VERSION 5.7 ;
  NOWIREEXTENSIONATPIN ON ;
  DIVIDERCHAR "/" ;
  BUSBITCHARS "[]" ;
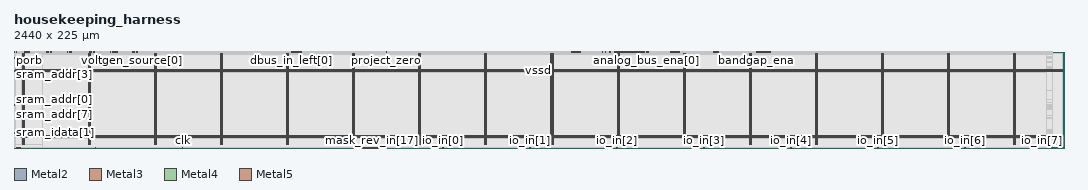
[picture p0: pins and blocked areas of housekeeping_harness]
MACRO housekeeping_harness
  CLASS BLOCK ;
  FOREIGN housekeeping_harness ;
  ORIGIN 0.000 0.000 ;
  SIZE 2440.000 BY 225.000 ;
  PIN CSB
    DIRECTION INPUT ;
    USE SIGNAL ;
    ANTENNAGATEAREA 0.666400 ;
    PORT
      LAYER Metal2 ;
        RECT 13.850 0.000 14.150 2.000 ;
    END
  END CSB
  PIN SCK
    DIRECTION INPUT ;
    USE SIGNAL ;
    ANTENNAGATEAREA 4.704000 ;
    PORT
      LAYER Metal2 ;
        RECT 188.850 0.000 189.150 2.000 ;
    END
  END SCK
  PIN SDI
    DIRECTION INPUT ;
    USE SIGNAL ;
    ANTENNAGATEAREA 0.666400 ;
    PORT
      LAYER Metal2 ;
        RECT 10.850 0.000 11.150 2.000 ;
    END
  END SDI
  PIN SDO
    DIRECTION OUTPUT ;
    USE SIGNAL ;
    ANTENNAGATEAREA 0.666400 ;
    ANTENNADIFFAREA 1.237600 ;
    PORT
      LAYER Metal2 ;
        RECT 4.850 0.000 5.150 2.000 ;
    END
  END SDO
  PIN analog_bus_ena[0]
    DIRECTION OUTPUT ;
    USE SIGNAL ;
    ANTENNADIFFAREA 4.368000 ;
    PORT
      LAYER Metal2 ;
        RECT 1468.850 223.000 1469.150 225.000 ;
    END
  END analog_bus_ena[0]
  PIN analog_bus_ena[1]
    DIRECTION OUTPUT ;
    USE SIGNAL ;
    ANTENNADIFFAREA 4.368000 ;
    PORT
      LAYER Metal2 ;
        RECT 1470.850 223.000 1471.150 225.000 ;
    END
  END analog_bus_ena[1]
  PIN analog_bus_ena[2]
    DIRECTION OUTPUT ;
    USE SIGNAL ;
    ANTENNADIFFAREA 4.368000 ;
    PORT
      LAYER Metal2 ;
        RECT 1472.850 223.000 1473.150 225.000 ;
    END
  END analog_bus_ena[2]
  PIN analog_bus_ena[3]
    DIRECTION OUTPUT ;
    USE SIGNAL ;
    ANTENNADIFFAREA 4.368000 ;
    PORT
      LAYER Metal2 ;
        RECT 1474.850 223.000 1475.150 225.000 ;
    END
  END analog_bus_ena[3]
  PIN bandgap_ena
    DIRECTION OUTPUT ;
    USE SIGNAL ;
    ANTENNADIFFAREA 1.237600 ;
    PORT
      LAYER Metal2 ;
        RECT 1724.850 223.000 1725.150 225.000 ;
    END
  END bandgap_ena
  PIN bandgap_sink1[0]
    DIRECTION OUTPUT ;
    USE SIGNAL ;
    ANTENNADIFFAREA 1.237600 ;
    PORT
      LAYER Metal2 ;
        RECT 174.850 223.000 175.150 225.000 ;
    END
  END bandgap_sink1[0]
  PIN bandgap_sink1[1]
    DIRECTION OUTPUT ;
    USE SIGNAL ;
    ANTENNADIFFAREA 1.237600 ;
    PORT
      LAYER Metal2 ;
        RECT 177.850 223.000 178.150 225.000 ;
    END
  END bandgap_sink1[1]
  PIN bandgap_sink1[2]
    DIRECTION OUTPUT ;
    USE SIGNAL ;
    ANTENNADIFFAREA 1.237600 ;
    PORT
      LAYER Metal2 ;
        RECT 180.850 223.000 181.150 225.000 ;
    END
  END bandgap_sink1[2]
  PIN bandgap_sink2[0]
    DIRECTION OUTPUT ;
    USE SIGNAL ;
    ANTENNADIFFAREA 1.237600 ;
    PORT
      LAYER Metal2 ;
        RECT 183.850 223.000 184.150 225.000 ;
    END
  END bandgap_sink2[0]
  PIN bandgap_sink2[1]
    DIRECTION OUTPUT ;
    USE SIGNAL ;
    ANTENNADIFFAREA 1.237600 ;
    PORT
      LAYER Metal2 ;
        RECT 186.850 223.000 187.150 225.000 ;
    END
  END bandgap_sink2[1]
  PIN bandgap_trim[0]
    DIRECTION OUTPUT ;
    USE SIGNAL ;
    ANTENNADIFFAREA 1.237600 ;
    PORT
      LAYER Metal2 ;
        RECT 1726.850 223.000 1727.150 225.000 ;
    END
  END bandgap_trim[0]
  PIN bandgap_trim[10]
    DIRECTION OUTPUT ;
    USE SIGNAL ;
    ANTENNADIFFAREA 1.237600 ;
    PORT
      LAYER Metal2 ;
        RECT 1746.850 223.000 1747.150 225.000 ;
    END
  END bandgap_trim[10]
  PIN bandgap_trim[11]
    DIRECTION OUTPUT ;
    USE SIGNAL ;
    ANTENNADIFFAREA 1.237600 ;
    PORT
      LAYER Metal2 ;
        RECT 1748.850 223.000 1749.150 225.000 ;
    END
  END bandgap_trim[11]
  PIN bandgap_trim[12]
    DIRECTION OUTPUT ;
    USE SIGNAL ;
    ANTENNADIFFAREA 1.237600 ;
    PORT
      LAYER Metal2 ;
        RECT 1750.850 223.000 1751.150 225.000 ;
    END
  END bandgap_trim[12]
  PIN bandgap_trim[13]
    DIRECTION OUTPUT ;
    USE SIGNAL ;
    ANTENNADIFFAREA 1.237600 ;
    PORT
      LAYER Metal2 ;
        RECT 1752.850 223.000 1753.150 225.000 ;
    END
  END bandgap_trim[13]
  PIN bandgap_trim[14]
    DIRECTION OUTPUT ;
    USE SIGNAL ;
    ANTENNADIFFAREA 1.237600 ;
    PORT
      LAYER Metal2 ;
        RECT 1754.850 223.000 1755.150 225.000 ;
    END
  END bandgap_trim[14]
  PIN bandgap_trim[15]
    DIRECTION OUTPUT ;
    USE SIGNAL ;
    ANTENNADIFFAREA 1.237600 ;
    PORT
      LAYER Metal2 ;
        RECT 1756.850 223.000 1757.150 225.000 ;
    END
  END bandgap_trim[15]
  PIN bandgap_trim[1]
    DIRECTION OUTPUT ;
    USE SIGNAL ;
    ANTENNADIFFAREA 1.237600 ;
    PORT
      LAYER Metal2 ;
        RECT 1728.850 223.000 1729.150 225.000 ;
    END
  END bandgap_trim[1]
  PIN bandgap_trim[2]
    DIRECTION OUTPUT ;
    USE SIGNAL ;
    ANTENNADIFFAREA 1.237600 ;
    PORT
      LAYER Metal2 ;
        RECT 1730.850 223.000 1731.150 225.000 ;
    END
  END bandgap_trim[2]
  PIN bandgap_trim[3]
    DIRECTION OUTPUT ;
    USE SIGNAL ;
    ANTENNADIFFAREA 1.237600 ;
    PORT
      LAYER Metal2 ;
        RECT 1732.850 223.000 1733.150 225.000 ;
    END
  END bandgap_trim[3]
  PIN bandgap_trim[4]
    DIRECTION OUTPUT ;
    USE SIGNAL ;
    ANTENNADIFFAREA 1.237600 ;
    PORT
      LAYER Metal2 ;
        RECT 1734.850 223.000 1735.150 225.000 ;
    END
  END bandgap_trim[4]
  PIN bandgap_trim[5]
    DIRECTION OUTPUT ;
    USE SIGNAL ;
    ANTENNADIFFAREA 1.237600 ;
    PORT
      LAYER Metal2 ;
        RECT 1736.850 223.000 1737.150 225.000 ;
    END
  END bandgap_trim[5]
  PIN bandgap_trim[6]
    DIRECTION OUTPUT ;
    USE SIGNAL ;
    ANTENNADIFFAREA 1.237600 ;
    PORT
      LAYER Metal2 ;
        RECT 1738.850 223.000 1739.150 225.000 ;
    END
  END bandgap_trim[6]
  PIN bandgap_trim[7]
    DIRECTION OUTPUT ;
    USE SIGNAL ;
    ANTENNADIFFAREA 1.237600 ;
    PORT
      LAYER Metal2 ;
        RECT 1740.850 223.000 1741.150 225.000 ;
    END
  END bandgap_trim[7]
  PIN bandgap_trim[8]
    DIRECTION OUTPUT ;
    USE SIGNAL ;
    ANTENNADIFFAREA 1.237600 ;
    PORT
      LAYER Metal2 ;
        RECT 1742.850 223.000 1743.150 225.000 ;
    END
  END bandgap_trim[8]
  PIN bandgap_trim[9]
    DIRECTION OUTPUT ;
    USE SIGNAL ;
    ANTENNADIFFAREA 1.237600 ;
    PORT
      LAYER Metal2 ;
        RECT 1744.850 223.000 1745.150 225.000 ;
    END
  END bandgap_trim[9]
  PIN biasgen_coarse
    DIRECTION OUTPUT ;
    USE SIGNAL ;
    ANTENNADIFFAREA 1.237600 ;
    PORT
      LAYER Metal2 ;
        RECT 127.850 223.000 128.150 225.000 ;
    END
  END biasgen_coarse
  PIN biasgen_ena
    DIRECTION OUTPUT ;
    USE SIGNAL ;
    ANTENNADIFFAREA 1.237600 ;
    PORT
      LAYER Metal2 ;
        RECT 124.850 223.000 125.150 225.000 ;
    END
  END biasgen_ena
  PIN biasgen_fine
    DIRECTION OUTPUT ;
    USE SIGNAL ;
    ANTENNADIFFAREA 1.237600 ;
    PORT
      LAYER Metal2 ;
        RECT 130.850 223.000 131.150 225.000 ;
    END
  END biasgen_fine
  PIN biasgen_ref_vbg
    DIRECTION OUTPUT ;
    USE SIGNAL ;
    ANTENNADIFFAREA 1.237600 ;
    PORT
      LAYER Metal2 ;
        RECT 133.850 223.000 134.150 225.000 ;
    END
  END biasgen_ref_vbg
  PIN clk
    DIRECTION INPUT ;
    USE SIGNAL ;
    ANTENNAGATEAREA 4.704000 ;
    PORT
      LAYER Metal2 ;
        RECT 391.850 0.000 392.150 2.000 ;
    END
  END clk
  PIN clk_out
    DIRECTION OUTPUT ;
    USE SIGNAL ;
    ANTENNADIFFAREA 6.583500 ;
    PORT
      LAYER Metal2 ;
        RECT 1374.850 223.000 1375.150 225.000 ;
    END
  END clk_out
  PIN dbus_in_left[0]
    DIRECTION INPUT ;
    USE SIGNAL ;
    ANTENNAGATEAREA 1.999200 ;
    ANTENNADIFFAREA 1.754000 ;
    PORT
      LAYER Metal2 ;
        RECT 644.850 223.000 645.150 225.000 ;
    END
  END dbus_in_left[0]
  PIN dbus_in_left[10]
    DIRECTION INPUT ;
    USE SIGNAL ;
    ANTENNAGATEAREA 1.999200 ;
    PORT
      LAYER Metal2 ;
        RECT 664.850 223.000 665.150 225.000 ;
    END
  END dbus_in_left[10]
  PIN dbus_in_left[11]
    DIRECTION INPUT ;
    USE SIGNAL ;
    ANTENNAGATEAREA 1.999200 ;
    PORT
      LAYER Metal2 ;
        RECT 666.850 223.000 667.150 225.000 ;
    END
  END dbus_in_left[11]
  PIN dbus_in_left[1]
    DIRECTION INPUT ;
    USE SIGNAL ;
    ANTENNAGATEAREA 1.999200 ;
    ANTENNADIFFAREA 1.754000 ;
    PORT
      LAYER Metal2 ;
        RECT 646.850 223.000 647.150 225.000 ;
    END
  END dbus_in_left[1]
  PIN dbus_in_left[2]
    DIRECTION INPUT ;
    USE SIGNAL ;
    ANTENNAGATEAREA 3.332000 ;
    PORT
      LAYER Metal2 ;
        RECT 648.850 223.000 649.150 225.000 ;
    END
  END dbus_in_left[2]
  PIN dbus_in_left[3]
    DIRECTION INPUT ;
    USE SIGNAL ;
    ANTENNAGATEAREA 1.999200 ;
    PORT
      LAYER Metal2 ;
        RECT 650.850 223.000 651.150 225.000 ;
    END
  END dbus_in_left[3]
  PIN dbus_in_left[4]
    DIRECTION INPUT ;
    USE SIGNAL ;
    ANTENNAGATEAREA 1.999200 ;
    ANTENNADIFFAREA 1.754000 ;
    PORT
      LAYER Metal2 ;
        RECT 652.850 223.000 653.150 225.000 ;
    END
  END dbus_in_left[4]
  PIN dbus_in_left[5]
    DIRECTION INPUT ;
    USE SIGNAL ;
    ANTENNAGATEAREA 1.999200 ;
    PORT
      LAYER Metal2 ;
        RECT 654.850 223.000 655.150 225.000 ;
    END
  END dbus_in_left[5]
  PIN dbus_in_left[6]
    DIRECTION INPUT ;
    USE SIGNAL ;
    ANTENNAGATEAREA 1.999200 ;
    ANTENNADIFFAREA 0.438500 ;
    PORT
      LAYER Metal2 ;
        RECT 656.850 223.000 657.150 225.000 ;
    END
  END dbus_in_left[6]
  PIN dbus_in_left[7]
    DIRECTION INPUT ;
    USE SIGNAL ;
    ANTENNAGATEAREA 1.999200 ;
    ANTENNADIFFAREA 1.754000 ;
    PORT
      LAYER Metal2 ;
        RECT 658.850 223.000 659.150 225.000 ;
    END
  END dbus_in_left[7]
  PIN dbus_in_left[8]
    DIRECTION INPUT ;
    USE SIGNAL ;
    ANTENNAGATEAREA 1.999200 ;
    PORT
      LAYER Metal2 ;
        RECT 660.850 223.000 661.150 225.000 ;
    END
  END dbus_in_left[8]
  PIN dbus_in_left[9]
    DIRECTION INPUT ;
    USE SIGNAL ;
    ANTENNAGATEAREA 1.999200 ;
    ANTENNADIFFAREA 1.754000 ;
    PORT
      LAYER Metal2 ;
        RECT 662.850 223.000 663.150 225.000 ;
    END
  END dbus_in_left[9]
  PIN dbus_in_right[0]
    DIRECTION INPUT ;
    USE SIGNAL ;
    ANTENNAGATEAREA 1.999200 ;
    PORT
      LAYER Metal2 ;
        RECT 1294.850 223.000 1295.150 225.000 ;
    END
  END dbus_in_right[0]
  PIN dbus_in_right[10]
    DIRECTION INPUT ;
    USE SIGNAL ;
    ANTENNAGATEAREA 1.999200 ;
    PORT
      LAYER Metal2 ;
        RECT 1314.850 223.000 1315.150 225.000 ;
    END
  END dbus_in_right[10]
  PIN dbus_in_right[11]
    DIRECTION INPUT ;
    USE SIGNAL ;
    ANTENNAGATEAREA 1.999200 ;
    PORT
      LAYER Metal2 ;
        RECT 1316.850 223.000 1317.150 225.000 ;
    END
  END dbus_in_right[11]
  PIN dbus_in_right[1]
    DIRECTION INPUT ;
    USE SIGNAL ;
    ANTENNAGATEAREA 1.999200 ;
    PORT
      LAYER Metal2 ;
        RECT 1296.850 223.000 1297.150 225.000 ;
    END
  END dbus_in_right[1]
  PIN dbus_in_right[2]
    DIRECTION INPUT ;
    USE SIGNAL ;
    ANTENNAGATEAREA 3.332000 ;
    PORT
      LAYER Metal2 ;
        RECT 1298.850 223.000 1299.150 225.000 ;
    END
  END dbus_in_right[2]
  PIN dbus_in_right[3]
    DIRECTION INPUT ;
    USE SIGNAL ;
    ANTENNAGATEAREA 1.999200 ;
    PORT
      LAYER Metal2 ;
        RECT 1300.850 223.000 1301.150 225.000 ;
    END
  END dbus_in_right[3]
  PIN dbus_in_right[4]
    DIRECTION INPUT ;
    USE SIGNAL ;
    ANTENNAGATEAREA 1.999200 ;
    PORT
      LAYER Metal2 ;
        RECT 1302.850 223.000 1303.150 225.000 ;
    END
  END dbus_in_right[4]
  PIN dbus_in_right[5]
    DIRECTION INPUT ;
    USE SIGNAL ;
    ANTENNAGATEAREA 1.999200 ;
    PORT
      LAYER Metal2 ;
        RECT 1304.850 223.000 1305.150 225.000 ;
    END
  END dbus_in_right[5]
  PIN dbus_in_right[6]
    DIRECTION INPUT ;
    USE SIGNAL ;
    ANTENNAGATEAREA 1.999200 ;
    PORT
      LAYER Metal2 ;
        RECT 1306.850 223.000 1307.150 225.000 ;
    END
  END dbus_in_right[6]
  PIN dbus_in_right[7]
    DIRECTION INPUT ;
    USE SIGNAL ;
    ANTENNAGATEAREA 1.999200 ;
    PORT
      LAYER Metal2 ;
        RECT 1308.850 223.000 1309.150 225.000 ;
    END
  END dbus_in_right[7]
  PIN dbus_in_right[8]
    DIRECTION INPUT ;
    USE SIGNAL ;
    ANTENNAGATEAREA 1.999200 ;
    PORT
      LAYER Metal2 ;
        RECT 1310.850 223.000 1311.150 225.000 ;
    END
  END dbus_in_right[8]
  PIN dbus_in_right[9]
    DIRECTION INPUT ;
    USE SIGNAL ;
    ANTENNAGATEAREA 1.999200 ;
    PORT
      LAYER Metal2 ;
        RECT 1312.850 223.000 1313.150 225.000 ;
    END
  END dbus_in_right[9]
  PIN dbus_out[0]
    DIRECTION OUTPUT ;
    USE SIGNAL ;
    ANTENNADIFFAREA 4.950400 ;
    PORT
      LAYER Metal2 ;
        RECT 1394.850 223.000 1395.150 225.000 ;
    END
  END dbus_out[0]
  PIN dbus_out[10]
    DIRECTION OUTPUT ;
    USE SIGNAL ;
    ANTENNADIFFAREA 4.950400 ;
    PORT
      LAYER Metal2 ;
        RECT 1414.850 223.000 1415.150 225.000 ;
    END
  END dbus_out[10]
  PIN dbus_out[11]
    DIRECTION OUTPUT ;
    USE SIGNAL ;
    ANTENNADIFFAREA 4.950400 ;
    PORT
      LAYER Metal2 ;
        RECT 1416.850 223.000 1417.150 225.000 ;
    END
  END dbus_out[11]
  PIN dbus_out[12]
    DIRECTION OUTPUT ;
    USE SIGNAL ;
    ANTENNADIFFAREA 4.950400 ;
    PORT
      LAYER Metal2 ;
        RECT 1418.850 223.000 1419.150 225.000 ;
    END
  END dbus_out[12]
  PIN dbus_out[13]
    DIRECTION OUTPUT ;
    USE SIGNAL ;
    ANTENNADIFFAREA 4.950400 ;
    PORT
      LAYER Metal2 ;
        RECT 1420.850 223.000 1421.150 225.000 ;
    END
  END dbus_out[13]
  PIN dbus_out[14]
    DIRECTION OUTPUT ;
    USE SIGNAL ;
    ANTENNADIFFAREA 4.950400 ;
    PORT
      LAYER Metal2 ;
        RECT 1422.850 223.000 1423.150 225.000 ;
    END
  END dbus_out[14]
  PIN dbus_out[15]
    DIRECTION OUTPUT ;
    USE SIGNAL ;
    ANTENNADIFFAREA 4.950400 ;
    PORT
      LAYER Metal2 ;
        RECT 1424.850 223.000 1425.150 225.000 ;
    END
  END dbus_out[15]
  PIN dbus_out[16]
    DIRECTION OUTPUT ;
    USE SIGNAL ;
    ANTENNADIFFAREA 4.950400 ;
    PORT
      LAYER Metal2 ;
        RECT 1426.850 223.000 1427.150 225.000 ;
    END
  END dbus_out[16]
  PIN dbus_out[17]
    DIRECTION OUTPUT ;
    USE SIGNAL ;
    ANTENNADIFFAREA 4.950400 ;
    PORT
      LAYER Metal2 ;
        RECT 1428.850 223.000 1429.150 225.000 ;
    END
  END dbus_out[17]
  PIN dbus_out[18]
    DIRECTION OUTPUT ;
    USE SIGNAL ;
    ANTENNADIFFAREA 4.950400 ;
    PORT
      LAYER Metal2 ;
        RECT 1430.850 223.000 1431.150 225.000 ;
    END
  END dbus_out[18]
  PIN dbus_out[19]
    DIRECTION OUTPUT ;
    USE SIGNAL ;
    ANTENNADIFFAREA 4.950400 ;
    PORT
      LAYER Metal2 ;
        RECT 1432.850 223.000 1433.150 225.000 ;
    END
  END dbus_out[19]
  PIN dbus_out[1]
    DIRECTION OUTPUT ;
    USE SIGNAL ;
    ANTENNADIFFAREA 4.950400 ;
    PORT
      LAYER Metal2 ;
        RECT 1396.850 223.000 1397.150 225.000 ;
    END
  END dbus_out[1]
  PIN dbus_out[20]
    DIRECTION OUTPUT ;
    USE SIGNAL ;
    ANTENNADIFFAREA 4.950400 ;
    PORT
      LAYER Metal2 ;
        RECT 1434.850 223.000 1435.150 225.000 ;
    END
  END dbus_out[20]
  PIN dbus_out[21]
    DIRECTION OUTPUT ;
    USE SIGNAL ;
    ANTENNADIFFAREA 4.950400 ;
    PORT
      LAYER Metal2 ;
        RECT 1436.850 223.000 1437.150 225.000 ;
    END
  END dbus_out[21]
  PIN dbus_out[22]
    DIRECTION OUTPUT ;
    USE SIGNAL ;
    ANTENNADIFFAREA 4.950400 ;
    PORT
      LAYER Metal2 ;
        RECT 1438.850 223.000 1439.150 225.000 ;
    END
  END dbus_out[22]
  PIN dbus_out[23]
    DIRECTION OUTPUT ;
    USE SIGNAL ;
    ANTENNADIFFAREA 4.950400 ;
    PORT
      LAYER Metal2 ;
        RECT 1440.850 223.000 1441.150 225.000 ;
    END
  END dbus_out[23]
  PIN dbus_out[2]
    DIRECTION OUTPUT ;
    USE SIGNAL ;
    ANTENNADIFFAREA 4.950400 ;
    PORT
      LAYER Metal2 ;
        RECT 1398.850 223.000 1399.150 225.000 ;
    END
  END dbus_out[2]
  PIN dbus_out[3]
    DIRECTION OUTPUT ;
    USE SIGNAL ;
    ANTENNADIFFAREA 4.950400 ;
    PORT
      LAYER Metal2 ;
        RECT 1400.850 223.000 1401.150 225.000 ;
    END
  END dbus_out[3]
  PIN dbus_out[4]
    DIRECTION OUTPUT ;
    USE SIGNAL ;
    ANTENNADIFFAREA 4.950400 ;
    PORT
      LAYER Metal2 ;
        RECT 1402.850 223.000 1403.150 225.000 ;
    END
  END dbus_out[4]
  PIN dbus_out[5]
    DIRECTION OUTPUT ;
    USE SIGNAL ;
    ANTENNADIFFAREA 4.950400 ;
    PORT
      LAYER Metal2 ;
        RECT 1404.850 223.000 1405.150 225.000 ;
    END
  END dbus_out[5]
  PIN dbus_out[6]
    DIRECTION OUTPUT ;
    USE SIGNAL ;
    ANTENNADIFFAREA 4.950400 ;
    PORT
      LAYER Metal2 ;
        RECT 1406.850 223.000 1407.150 225.000 ;
    END
  END dbus_out[6]
  PIN dbus_out[7]
    DIRECTION OUTPUT ;
    USE SIGNAL ;
    ANTENNADIFFAREA 4.950400 ;
    PORT
      LAYER Metal2 ;
        RECT 1408.850 223.000 1409.150 225.000 ;
    END
  END dbus_out[7]
  PIN dbus_out[8]
    DIRECTION OUTPUT ;
    USE SIGNAL ;
    ANTENNADIFFAREA 4.950400 ;
    PORT
      LAYER Metal2 ;
        RECT 1410.850 223.000 1411.150 225.000 ;
    END
  END dbus_out[8]
  PIN dbus_out[9]
    DIRECTION OUTPUT ;
    USE SIGNAL ;
    ANTENNADIFFAREA 4.950400 ;
    PORT
      LAYER Metal2 ;
        RECT 1412.850 223.000 1413.150 225.000 ;
    END
  END dbus_out[9]
  PIN idac1_value[0]
    DIRECTION OUTPUT ;
    USE SIGNAL ;
    ANTENNADIFFAREA 1.237600 ;
    PORT
      LAYER Metal2 ;
        RECT 24.850 223.000 25.150 225.000 ;
    END
  END idac1_value[0]
  PIN idac1_value[1]
    DIRECTION OUTPUT ;
    USE SIGNAL ;
    ANTENNADIFFAREA 1.237600 ;
    PORT
      LAYER Metal2 ;
        RECT 27.850 223.000 28.150 225.000 ;
    END
  END idac1_value[1]
  PIN idac1_value[2]
    DIRECTION OUTPUT ;
    USE SIGNAL ;
    ANTENNADIFFAREA 1.237600 ;
    PORT
      LAYER Metal2 ;
        RECT 30.850 223.000 31.150 225.000 ;
    END
  END idac1_value[2]
  PIN idac1_value[3]
    DIRECTION OUTPUT ;
    USE SIGNAL ;
    ANTENNADIFFAREA 1.237600 ;
    PORT
      LAYER Metal2 ;
        RECT 33.850 223.000 34.150 225.000 ;
    END
  END idac1_value[3]
  PIN idac1_value[4]
    DIRECTION OUTPUT ;
    USE SIGNAL ;
    ANTENNADIFFAREA 1.237600 ;
    PORT
      LAYER Metal2 ;
        RECT 36.850 223.000 37.150 225.000 ;
    END
  END idac1_value[4]
  PIN idac2_value[0]
    DIRECTION OUTPUT ;
    USE SIGNAL ;
    ANTENNADIFFAREA 1.237600 ;
    PORT
      LAYER Metal2 ;
        RECT 74.850 223.000 75.150 225.000 ;
    END
  END idac2_value[0]
  PIN idac2_value[1]
    DIRECTION OUTPUT ;
    USE SIGNAL ;
    ANTENNADIFFAREA 1.237600 ;
    PORT
      LAYER Metal2 ;
        RECT 77.850 223.000 78.150 225.000 ;
    END
  END idac2_value[1]
  PIN idac2_value[2]
    DIRECTION OUTPUT ;
    USE SIGNAL ;
    ANTENNADIFFAREA 1.237600 ;
    PORT
      LAYER Metal2 ;
        RECT 80.850 223.000 81.150 225.000 ;
    END
  END idac2_value[2]
  PIN idac2_value[3]
    DIRECTION OUTPUT ;
    USE SIGNAL ;
    ANTENNADIFFAREA 1.237600 ;
    PORT
      LAYER Metal2 ;
        RECT 83.850 223.000 84.150 225.000 ;
    END
  END idac2_value[3]
  PIN idac2_value[4]
    DIRECTION OUTPUT ;
    USE SIGNAL ;
    ANTENNADIFFAREA 1.237600 ;
    PORT
      LAYER Metal2 ;
        RECT 86.850 223.000 87.150 225.000 ;
    END
  END idac2_value[4]
  PIN io_in[0]
    DIRECTION INPUT ;
    USE SIGNAL ;
    ANTENNAGATEAREA 0.666400 ;
    PORT
      LAYER Metal2 ;
        RECT 997.850 0.000 998.150 2.000 ;
    END
  END io_in[0]
  PIN io_in[10]
    DIRECTION INPUT ;
    USE SIGNAL ;
    ANTENNAGATEAREA 1.332800 ;
    PORT
      LAYER Metal2 ;
        RECT 1540.850 223.000 1541.150 225.000 ;
    END
  END io_in[10]
  PIN io_in[11]
    DIRECTION INPUT ;
    USE SIGNAL ;
    ANTENNAGATEAREA 0.666400 ;
    PORT
      LAYER Metal2 ;
        RECT 1546.850 223.000 1547.150 225.000 ;
    END
  END io_in[11]
  PIN io_in[1]
    DIRECTION INPUT ;
    USE SIGNAL ;
    ANTENNAGATEAREA 0.666400 ;
    PORT
      LAYER Metal2 ;
        RECT 1199.850 0.000 1200.150 2.000 ;
    END
  END io_in[1]
  PIN io_in[2]
    DIRECTION INPUT ;
    USE SIGNAL ;
    ANTENNAGATEAREA 1.332800 ;
    PORT
      LAYER Metal2 ;
        RECT 1401.850 0.000 1402.150 2.000 ;
    END
  END io_in[2]
  PIN io_in[3]
    DIRECTION INPUT ;
    USE SIGNAL ;
    ANTENNAGATEAREA 0.666400 ;
    PORT
      LAYER Metal2 ;
        RECT 1603.850 0.000 1604.150 2.000 ;
    END
  END io_in[3]
  PIN io_in[4]
    DIRECTION INPUT ;
    USE SIGNAL ;
    ANTENNAGATEAREA 1.332800 ;
    PORT
      LAYER Metal2 ;
        RECT 1805.850 0.000 1806.150 2.000 ;
    END
  END io_in[4]
  PIN io_in[5]
    DIRECTION INPUT ;
    USE SIGNAL ;
    ANTENNAGATEAREA 1.332800 ;
    PORT
      LAYER Metal2 ;
        RECT 2007.850 0.000 2008.150 2.000 ;
    END
  END io_in[5]
  PIN io_in[6]
    DIRECTION INPUT ;
    USE SIGNAL ;
    ANTENNAGATEAREA 0.666400 ;
    PORT
      LAYER Metal2 ;
        RECT 2209.850 0.000 2210.150 2.000 ;
    END
  END io_in[6]
  PIN io_in[7]
    DIRECTION INPUT ;
    USE SIGNAL ;
    ANTENNAGATEAREA 0.666400 ;
    PORT
      LAYER Metal2 ;
        RECT 2411.850 0.000 2412.150 2.000 ;
    END
  END io_in[7]
  PIN io_in[8]
    DIRECTION INPUT ;
    USE SIGNAL ;
    ANTENNAGATEAREA 1.332800 ;
    ANTENNADIFFAREA 0.877000 ;
    PORT
      LAYER Metal2 ;
        RECT 1528.850 223.000 1529.150 225.000 ;
    END
  END io_in[8]
  PIN io_in[9]
    DIRECTION INPUT ;
    USE SIGNAL ;
    ANTENNAGATEAREA 1.332800 ;
    PORT
      LAYER Metal2 ;
        RECT 1534.850 223.000 1535.150 225.000 ;
    END
  END io_in[9]
  PIN io_oe[0]
    DIRECTION OUTPUT ;
    USE SIGNAL ;
    ANTENNADIFFAREA 1.237600 ;
    PORT
      LAYER Metal2 ;
        RECT 996.850 0.000 997.150 2.000 ;
    END
  END io_oe[0]
  PIN io_oe[10]
    DIRECTION OUTPUT ;
    USE SIGNAL ;
    ANTENNADIFFAREA 1.237600 ;
    PORT
      LAYER Metal2 ;
        RECT 1538.850 223.000 1539.150 225.000 ;
    END
  END io_oe[10]
  PIN io_oe[11]
    DIRECTION OUTPUT ;
    USE SIGNAL ;
    ANTENNADIFFAREA 1.237600 ;
    PORT
      LAYER Metal2 ;
        RECT 1544.850 223.000 1545.150 225.000 ;
    END
  END io_oe[11]
  PIN io_oe[1]
    DIRECTION OUTPUT ;
    USE SIGNAL ;
    ANTENNADIFFAREA 1.237600 ;
    PORT
      LAYER Metal2 ;
        RECT 1198.850 0.000 1199.150 2.000 ;
    END
  END io_oe[1]
  PIN io_oe[2]
    DIRECTION OUTPUT ;
    USE SIGNAL ;
    ANTENNADIFFAREA 1.237600 ;
    PORT
      LAYER Metal2 ;
        RECT 1400.850 0.000 1401.150 2.000 ;
    END
  END io_oe[2]
  PIN io_oe[3]
    DIRECTION OUTPUT ;
    USE SIGNAL ;
    ANTENNADIFFAREA 1.237600 ;
    PORT
      LAYER Metal2 ;
        RECT 1602.850 0.000 1603.150 2.000 ;
    END
  END io_oe[3]
  PIN io_oe[4]
    DIRECTION OUTPUT ;
    USE SIGNAL ;
    ANTENNADIFFAREA 1.237600 ;
    PORT
      LAYER Metal2 ;
        RECT 1804.850 0.000 1805.150 2.000 ;
    END
  END io_oe[4]
  PIN io_oe[5]
    DIRECTION OUTPUT ;
    USE SIGNAL ;
    ANTENNADIFFAREA 1.237600 ;
    PORT
      LAYER Metal2 ;
        RECT 2006.850 0.000 2007.150 2.000 ;
    END
  END io_oe[5]
  PIN io_oe[6]
    DIRECTION OUTPUT ;
    USE SIGNAL ;
    ANTENNADIFFAREA 1.237600 ;
    PORT
      LAYER Metal2 ;
        RECT 2208.850 0.000 2209.150 2.000 ;
    END
  END io_oe[6]
  PIN io_oe[7]
    DIRECTION OUTPUT ;
    USE SIGNAL ;
    ANTENNADIFFAREA 1.237600 ;
    PORT
      LAYER Metal2 ;
        RECT 2410.850 0.000 2411.150 2.000 ;
    END
  END io_oe[7]
  PIN io_oe[8]
    DIRECTION OUTPUT ;
    USE SIGNAL ;
    ANTENNADIFFAREA 1.237600 ;
    PORT
      LAYER Metal2 ;
        RECT 1526.850 223.000 1527.150 225.000 ;
    END
  END io_oe[8]
  PIN io_oe[9]
    DIRECTION OUTPUT ;
    USE SIGNAL ;
    ANTENNADIFFAREA 1.237600 ;
    PORT
      LAYER Metal2 ;
        RECT 1532.850 223.000 1533.150 225.000 ;
    END
  END io_oe[9]
  PIN io_out[0]
    DIRECTION OUTPUT ;
    USE SIGNAL ;
    ANTENNADIFFAREA 4.950400 ;
    PORT
      LAYER Metal2 ;
        RECT 995.850 0.000 996.150 2.000 ;
    END
  END io_out[0]
  PIN io_out[10]
    DIRECTION OUTPUT ;
    USE SIGNAL ;
    ANTENNADIFFAREA 1.237600 ;
    PORT
      LAYER Metal2 ;
        RECT 1536.850 223.000 1537.150 225.000 ;
    END
  END io_out[10]
  PIN io_out[11]
    DIRECTION OUTPUT ;
    USE SIGNAL ;
    ANTENNADIFFAREA 4.950400 ;
    PORT
      LAYER Metal2 ;
        RECT 1542.850 223.000 1543.150 225.000 ;
    END
  END io_out[11]
  PIN io_out[1]
    DIRECTION OUTPUT ;
    USE SIGNAL ;
    ANTENNADIFFAREA 4.950400 ;
    PORT
      LAYER Metal2 ;
        RECT 1197.850 0.000 1198.150 2.000 ;
    END
  END io_out[1]
  PIN io_out[2]
    DIRECTION OUTPUT ;
    USE SIGNAL ;
    ANTENNADIFFAREA 4.950400 ;
    PORT
      LAYER Metal2 ;
        RECT 1399.850 0.000 1400.150 2.000 ;
    END
  END io_out[2]
  PIN io_out[3]
    DIRECTION OUTPUT ;
    USE SIGNAL ;
    ANTENNADIFFAREA 4.950400 ;
    PORT
      LAYER Metal2 ;
        RECT 1601.850 0.000 1602.150 2.000 ;
    END
  END io_out[3]
  PIN io_out[4]
    DIRECTION OUTPUT ;
    USE SIGNAL ;
    ANTENNADIFFAREA 4.950400 ;
    PORT
      LAYER Metal2 ;
        RECT 1803.850 0.000 1804.150 2.000 ;
    END
  END io_out[4]
  PIN io_out[5]
    DIRECTION OUTPUT ;
    USE SIGNAL ;
    ANTENNADIFFAREA 4.950400 ;
    PORT
      LAYER Metal2 ;
        RECT 2005.850 0.000 2006.150 2.000 ;
    END
  END io_out[5]
  PIN io_out[6]
    DIRECTION OUTPUT ;
    USE SIGNAL ;
    ANTENNADIFFAREA 1.237600 ;
    PORT
      LAYER Metal2 ;
        RECT 2207.850 0.000 2208.150 2.000 ;
    END
  END io_out[6]
  PIN io_out[7]
    DIRECTION OUTPUT ;
    USE SIGNAL ;
    ANTENNADIFFAREA 4.950400 ;
    PORT
      LAYER Metal2 ;
        RECT 2409.850 0.000 2410.150 2.000 ;
    END
  END io_out[7]
  PIN io_out[8]
    DIRECTION OUTPUT ;
    USE SIGNAL ;
    ANTENNADIFFAREA 4.950400 ;
    PORT
      LAYER Metal2 ;
        RECT 1524.850 223.000 1525.150 225.000 ;
    END
  END io_out[8]
  PIN io_out[9]
    DIRECTION OUTPUT ;
    USE SIGNAL ;
    ANTENNADIFFAREA 4.950400 ;
    PORT
      LAYER Metal2 ;
        RECT 1530.850 223.000 1531.150 225.000 ;
    END
  END io_out[9]
  PIN mask_rev_in[0]
    DIRECTION INPUT ;
    USE SIGNAL ;
    ANTENNAGATEAREA 0.666400 ;
    PORT
      LAYER Metal2 ;
        RECT 866.850 0.000 867.150 2.000 ;
    END
  END mask_rev_in[0]
  PIN mask_rev_in[10]
    DIRECTION INPUT ;
    USE SIGNAL ;
    ANTENNAGATEAREA 0.666400 ;
    PORT
      LAYER Metal2 ;
        RECT 846.850 0.000 847.150 2.000 ;
    END
  END mask_rev_in[10]
  PIN mask_rev_in[11]
    DIRECTION INPUT ;
    USE SIGNAL ;
    ANTENNAGATEAREA 0.666400 ;
    PORT
      LAYER Metal2 ;
        RECT 844.850 0.000 845.150 2.000 ;
    END
  END mask_rev_in[11]
  PIN mask_rev_in[12]
    DIRECTION INPUT ;
    USE SIGNAL ;
    ANTENNAGATEAREA 0.666400 ;
    PORT
      LAYER Metal2 ;
        RECT 842.850 0.000 843.150 2.000 ;
    END
  END mask_rev_in[12]
  PIN mask_rev_in[13]
    DIRECTION INPUT ;
    USE SIGNAL ;
    ANTENNAGATEAREA 0.666400 ;
    PORT
      LAYER Metal2 ;
        RECT 840.850 0.000 841.150 2.000 ;
    END
  END mask_rev_in[13]
  PIN mask_rev_in[14]
    DIRECTION INPUT ;
    USE SIGNAL ;
    ANTENNAGATEAREA 0.666400 ;
    PORT
      LAYER Metal2 ;
        RECT 838.850 0.000 839.150 2.000 ;
    END
  END mask_rev_in[14]
  PIN mask_rev_in[15]
    DIRECTION INPUT ;
    USE SIGNAL ;
    ANTENNAGATEAREA 0.666400 ;
    PORT
      LAYER Metal2 ;
        RECT 836.850 0.000 837.150 2.000 ;
    END
  END mask_rev_in[15]
  PIN mask_rev_in[16]
    DIRECTION INPUT ;
    USE SIGNAL ;
    ANTENNAGATEAREA 0.666400 ;
    PORT
      LAYER Metal2 ;
        RECT 834.850 0.000 835.150 2.000 ;
    END
  END mask_rev_in[16]
  PIN mask_rev_in[17]
    DIRECTION INPUT ;
    USE SIGNAL ;
    ANTENNAGATEAREA 0.666400 ;
    PORT
      LAYER Metal2 ;
        RECT 832.850 0.000 833.150 2.000 ;
    END
  END mask_rev_in[17]
  PIN mask_rev_in[18]
    DIRECTION INPUT ;
    USE SIGNAL ;
    ANTENNAGATEAREA 0.666400 ;
    PORT
      LAYER Metal2 ;
        RECT 830.850 0.000 831.150 2.000 ;
    END
  END mask_rev_in[18]
  PIN mask_rev_in[19]
    DIRECTION INPUT ;
    USE SIGNAL ;
    ANTENNAGATEAREA 0.666400 ;
    PORT
      LAYER Metal2 ;
        RECT 828.850 0.000 829.150 2.000 ;
    END
  END mask_rev_in[19]
  PIN mask_rev_in[1]
    DIRECTION INPUT ;
    USE SIGNAL ;
    ANTENNAGATEAREA 0.666400 ;
    PORT
      LAYER Metal2 ;
        RECT 864.850 0.000 865.150 2.000 ;
    END
  END mask_rev_in[1]
  PIN mask_rev_in[20]
    DIRECTION INPUT ;
    USE SIGNAL ;
    ANTENNAGATEAREA 0.666400 ;
    PORT
      LAYER Metal2 ;
        RECT 826.850 0.000 827.150 2.000 ;
    END
  END mask_rev_in[20]
  PIN mask_rev_in[21]
    DIRECTION INPUT ;
    USE SIGNAL ;
    ANTENNAGATEAREA 0.666400 ;
    PORT
      LAYER Metal2 ;
        RECT 824.850 0.000 825.150 2.000 ;
    END
  END mask_rev_in[21]
  PIN mask_rev_in[22]
    DIRECTION INPUT ;
    USE SIGNAL ;
    ANTENNAGATEAREA 0.666400 ;
    PORT
      LAYER Metal2 ;
        RECT 822.850 0.000 823.150 2.000 ;
    END
  END mask_rev_in[22]
  PIN mask_rev_in[23]
    DIRECTION INPUT ;
    USE SIGNAL ;
    ANTENNAGATEAREA 0.666400 ;
    PORT
      LAYER Metal2 ;
        RECT 820.850 0.000 821.150 2.000 ;
    END
  END mask_rev_in[23]
  PIN mask_rev_in[24]
    DIRECTION INPUT ;
    USE SIGNAL ;
    ANTENNAGATEAREA 0.666400 ;
    ANTENNADIFFAREA 0.877000 ;
    PORT
      LAYER Metal2 ;
        RECT 818.850 0.000 819.150 2.000 ;
    END
  END mask_rev_in[24]
  PIN mask_rev_in[25]
    DIRECTION INPUT ;
    USE SIGNAL ;
    ANTENNAGATEAREA 0.666400 ;
    PORT
      LAYER Metal2 ;
        RECT 816.850 0.000 817.150 2.000 ;
    END
  END mask_rev_in[25]
  PIN mask_rev_in[26]
    DIRECTION INPUT ;
    USE SIGNAL ;
    ANTENNAGATEAREA 0.666400 ;
    PORT
      LAYER Metal2 ;
        RECT 814.850 0.000 815.150 2.000 ;
    END
  END mask_rev_in[26]
  PIN mask_rev_in[27]
    DIRECTION INPUT ;
    USE SIGNAL ;
    ANTENNAGATEAREA 0.666400 ;
    PORT
      LAYER Metal2 ;
        RECT 812.850 0.000 813.150 2.000 ;
    END
  END mask_rev_in[27]
  PIN mask_rev_in[28]
    DIRECTION INPUT ;
    USE SIGNAL ;
    ANTENNAGATEAREA 0.666400 ;
    PORT
      LAYER Metal2 ;
        RECT 810.850 0.000 811.150 2.000 ;
    END
  END mask_rev_in[28]
  PIN mask_rev_in[29]
    DIRECTION INPUT ;
    USE SIGNAL ;
    ANTENNAGATEAREA 0.666400 ;
    PORT
      LAYER Metal2 ;
        RECT 808.850 0.000 809.150 2.000 ;
    END
  END mask_rev_in[29]
  PIN mask_rev_in[2]
    DIRECTION INPUT ;
    USE SIGNAL ;
    ANTENNAGATEAREA 0.666400 ;
    PORT
      LAYER Metal2 ;
        RECT 862.850 0.000 863.150 2.000 ;
    END
  END mask_rev_in[2]
  PIN mask_rev_in[30]
    DIRECTION INPUT ;
    USE SIGNAL ;
    ANTENNAGATEAREA 0.666400 ;
    PORT
      LAYER Metal2 ;
        RECT 806.850 0.000 807.150 2.000 ;
    END
  END mask_rev_in[30]
  PIN mask_rev_in[31]
    DIRECTION INPUT ;
    USE SIGNAL ;
    ANTENNAGATEAREA 0.666400 ;
    PORT
      LAYER Metal2 ;
        RECT 804.850 0.000 805.150 2.000 ;
    END
  END mask_rev_in[31]
  PIN mask_rev_in[3]
    DIRECTION INPUT ;
    USE SIGNAL ;
    ANTENNAGATEAREA 0.666400 ;
    PORT
      LAYER Metal2 ;
        RECT 860.850 0.000 861.150 2.000 ;
    END
  END mask_rev_in[3]
  PIN mask_rev_in[4]
    DIRECTION INPUT ;
    USE SIGNAL ;
    ANTENNAGATEAREA 0.666400 ;
    PORT
      LAYER Metal2 ;
        RECT 858.850 0.000 859.150 2.000 ;
    END
  END mask_rev_in[4]
  PIN mask_rev_in[5]
    DIRECTION INPUT ;
    USE SIGNAL ;
    ANTENNAGATEAREA 0.666400 ;
    PORT
      LAYER Metal2 ;
        RECT 856.850 0.000 857.150 2.000 ;
    END
  END mask_rev_in[5]
  PIN mask_rev_in[6]
    DIRECTION INPUT ;
    USE SIGNAL ;
    ANTENNAGATEAREA 0.666400 ;
    PORT
      LAYER Metal2 ;
        RECT 854.850 0.000 855.150 2.000 ;
    END
  END mask_rev_in[6]
  PIN mask_rev_in[7]
    DIRECTION INPUT ;
    USE SIGNAL ;
    ANTENNAGATEAREA 0.666400 ;
    PORT
      LAYER Metal2 ;
        RECT 852.850 0.000 853.150 2.000 ;
    END
  END mask_rev_in[7]
  PIN mask_rev_in[8]
    DIRECTION INPUT ;
    USE SIGNAL ;
    ANTENNAGATEAREA 0.666400 ;
    ANTENNADIFFAREA 1.315500 ;
    PORT
      LAYER Metal2 ;
        RECT 850.850 0.000 851.150 2.000 ;
    END
  END mask_rev_in[8]
  PIN mask_rev_in[9]
    DIRECTION INPUT ;
    USE SIGNAL ;
    ANTENNAGATEAREA 0.666400 ;
    ANTENNADIFFAREA 1.315500 ;
    PORT
      LAYER Metal2 ;
        RECT 848.850 0.000 849.150 2.000 ;
    END
  END mask_rev_in[9]
  PIN porb
    DIRECTION INPUT ;
    USE SIGNAL ;
    ANTENNAGATEAREA 1.332800 ;
    ANTENNADIFFAREA 3.508000 ;
    PORT
      LAYER Metal2 ;
        RECT 4.850 223.000 5.150 225.000 ;
    END
  END porb
  PIN proj_3v3_ena
    DIRECTION OUTPUT ;
    USE SIGNAL ;
    ANTENNADIFFAREA 4.368000 ;
    PORT
      LAYER Metal2 ;
        RECT 1460.850 223.000 1461.150 225.000 ;
    END
  END proj_3v3_ena
  PIN proj_5v0_ena
    DIRECTION OUTPUT ;
    USE SIGNAL ;
    ANTENNADIFFAREA 4.368000 ;
    PORT
      LAYER Metal2 ;
        RECT 1458.850 223.000 1459.150 225.000 ;
    END
  END proj_5v0_ena
  PIN proj_dig_ena
    DIRECTION OUTPUT ;
    USE SIGNAL ;
    ANTENNADIFFAREA 4.368000 ;
    PORT
      LAYER Metal2 ;
        RECT 1456.850 223.000 1457.150 225.000 ;
    END
  END proj_dig_ena
  PIN proj_ena
    DIRECTION OUTPUT ;
    USE SIGNAL ;
    ANTENNADIFFAREA 4.368000 ;
    PORT
      LAYER Metal2 ;
        RECT 1454.850 223.000 1455.150 225.000 ;
    END
  END proj_ena
  PIN proj_ibias_ena[0]
    DIRECTION OUTPUT ;
    USE SIGNAL ;
    ANTENNADIFFAREA 4.368000 ;
    PORT
      LAYER Metal2 ;
        RECT 1462.850 223.000 1463.150 225.000 ;
    END
  END proj_ibias_ena[0]
  PIN proj_ibias_ena[1]
    DIRECTION OUTPUT ;
    USE SIGNAL ;
    ANTENNADIFFAREA 4.368000 ;
    PORT
      LAYER Metal2 ;
        RECT 1464.850 223.000 1465.150 225.000 ;
    END
  END proj_ibias_ena[1]
  PIN proj_sel[0]
    DIRECTION OUTPUT ;
    USE SIGNAL ;
    ANTENNADIFFAREA 4.368000 ;
    PORT
      LAYER Metal2 ;
        RECT 1444.850 223.000 1445.150 225.000 ;
    END
  END proj_sel[0]
  PIN proj_sel[1]
    DIRECTION OUTPUT ;
    USE SIGNAL ;
    ANTENNADIFFAREA 4.368000 ;
    PORT
      LAYER Metal2 ;
        RECT 1446.850 223.000 1447.150 225.000 ;
    END
  END proj_sel[1]
  PIN proj_sel[2]
    DIRECTION OUTPUT ;
    USE SIGNAL ;
    ANTENNADIFFAREA 4.368000 ;
    PORT
      LAYER Metal2 ;
        RECT 1448.850 223.000 1449.150 225.000 ;
    END
  END proj_sel[2]
  PIN proj_sel[3]
    DIRECTION OUTPUT ;
    USE SIGNAL ;
    ANTENNADIFFAREA 4.368000 ;
    PORT
      LAYER Metal2 ;
        RECT 1450.850 223.000 1451.150 225.000 ;
    END
  END proj_sel[3]
  PIN proj_sel[4]
    DIRECTION OUTPUT ;
    USE SIGNAL ;
    ANTENNADIFFAREA 4.368000 ;
    PORT
      LAYER Metal2 ;
        RECT 1452.850 223.000 1453.150 225.000 ;
    END
  END proj_sel[4]
  PIN proj_vbias_ena
    DIRECTION OUTPUT ;
    USE SIGNAL ;
    ANTENNADIFFAREA 4.368000 ;
    PORT
      LAYER Metal2 ;
        RECT 1366.850 223.000 1367.150 225.000 ;
    END
  END proj_vbias_ena
  PIN project_zero
    DIRECTION OUTPUT ;
    USE SIGNAL ;
    ANTENNADIFFAREA 1.237600 ;
    PORT
      LAYER Metal2 ;
        RECT 864.850 223.000 865.150 225.000 ;
    END
  END project_zero
  PIN reset
    DIRECTION OUTPUT ;
    USE SIGNAL ;
    ANTENNADIFFAREA 4.368000 ;
    PORT
      LAYER Metal2 ;
        RECT 1384.850 223.000 1385.150 225.000 ;
    END
  END reset
  PIN sdo_ena
    DIRECTION OUTPUT ;
    USE SIGNAL ;
    ANTENNADIFFAREA 1.237600 ;
    PORT
      LAYER Metal2 ;
        RECT 7.850 0.000 8.150 2.000 ;
    END
  END sdo_ena
  PIN sram_addr[0]
    DIRECTION OUTPUT ;
    USE SIGNAL ;
    ANTENNADIFFAREA 1.237600 ;
    PORT
      LAYER Metal3 ;
        RECT 0.000 111.850 2.000 112.150 ;
    END
  END sram_addr[0]
  PIN sram_addr[1]
    DIRECTION OUTPUT ;
    USE SIGNAL ;
    ANTENNADIFFAREA 1.237600 ;
    PORT
      LAYER Metal3 ;
        RECT 0.000 105.850 2.000 106.150 ;
    END
  END sram_addr[1]
  PIN sram_addr[2]
    DIRECTION OUTPUT ;
    USE SIGNAL ;
    ANTENNADIFFAREA 1.237600 ;
    PORT
      LAYER Metal3 ;
        RECT 0.000 99.850 2.000 100.150 ;
    END
  END sram_addr[2]
  PIN sram_addr[3]
    DIRECTION OUTPUT ;
    USE SIGNAL ;
    ANTENNADIFFAREA 1.237600 ;
    PORT
      LAYER Metal3 ;
        RECT 0.000 188.850 2.000 189.150 ;
    END
  END sram_addr[3]
  PIN sram_addr[4]
    DIRECTION OUTPUT ;
    USE SIGNAL ;
    ANTENNADIFFAREA 1.237600 ;
    PORT
      LAYER Metal3 ;
        RECT 0.000 184.850 2.000 185.150 ;
    END
  END sram_addr[4]
  PIN sram_addr[5]
    DIRECTION OUTPUT ;
    USE SIGNAL ;
    ANTENNADIFFAREA 1.237600 ;
    PORT
      LAYER Metal3 ;
        RECT 0.000 182.850 2.000 183.150 ;
    END
  END sram_addr[5]
  PIN sram_addr[6]
    DIRECTION OUTPUT ;
    USE SIGNAL ;
    ANTENNADIFFAREA 1.237600 ;
    PORT
      LAYER Metal3 ;
        RECT 0.000 180.850 2.000 181.150 ;
    END
  END sram_addr[6]
  PIN sram_addr[7]
    DIRECTION OUTPUT ;
    USE SIGNAL ;
    ANTENNADIFFAREA 1.237600 ;
    PORT
      LAYER Metal3 ;
        RECT 0.000 95.850 2.000 96.150 ;
    END
  END sram_addr[7]
  PIN sram_addr[8]
    DIRECTION OUTPUT ;
    USE SIGNAL ;
    ANTENNADIFFAREA 1.237600 ;
    PORT
      LAYER Metal3 ;
        RECT 0.000 93.850 2.000 94.150 ;
    END
  END sram_addr[8]
  PIN sram_addr[9]
    DIRECTION OUTPUT ;
    USE SIGNAL ;
    ANTENNADIFFAREA 1.237600 ;
    PORT
      LAYER Metal3 ;
        RECT 0.000 91.850 2.000 92.150 ;
    END
  END sram_addr[9]
  PIN sram_clk
    DIRECTION OUTPUT ;
    USE SIGNAL ;
    ANTENNADIFFAREA 1.285200 ;
    PORT
      LAYER Metal3 ;
        RECT 0.000 89.850 2.000 90.150 ;
    END
  END sram_clk
  PIN sram_idata[0]
    DIRECTION OUTPUT ;
    USE SIGNAL ;
    ANTENNADIFFAREA 1.237600 ;
    PORT
      LAYER Metal3 ;
        RECT 0.000 0.850 2.000 1.150 ;
    END
  END sram_idata[0]
  PIN sram_idata[1]
    DIRECTION OUTPUT ;
    USE SIGNAL ;
    ANTENNADIFFAREA 1.237600 ;
    PORT
      LAYER Metal3 ;
        RECT 0.000 34.850 2.000 35.150 ;
    END
  END sram_idata[1]
  PIN sram_idata[2]
    DIRECTION OUTPUT ;
    USE SIGNAL ;
    ANTENNADIFFAREA 1.237600 ;
    PORT
      LAYER Metal3 ;
        RECT 0.000 38.850 2.000 39.150 ;
    END
  END sram_idata[2]
  PIN sram_idata[3]
    DIRECTION OUTPUT ;
    USE SIGNAL ;
    ANTENNADIFFAREA 1.237600 ;
    PORT
      LAYER Metal3 ;
        RECT 0.000 74.850 2.000 75.150 ;
    END
  END sram_idata[3]
  PIN sram_idata[4]
    DIRECTION OUTPUT ;
    USE SIGNAL ;
    ANTENNADIFFAREA 1.237600 ;
    PORT
      LAYER Metal3 ;
        RECT 0.000 208.850 2.000 209.150 ;
    END
  END sram_idata[4]
  PIN sram_idata[5]
    DIRECTION OUTPUT ;
    USE SIGNAL ;
    ANTENNADIFFAREA 1.237600 ;
    PORT
      LAYER Metal3 ;
        RECT 0.000 181.850 2.000 182.150 ;
    END
  END sram_idata[5]
  PIN sram_idata[6]
    DIRECTION OUTPUT ;
    USE SIGNAL ;
    ANTENNADIFFAREA 1.237600 ;
    PORT
      LAYER Metal3 ;
        RECT 0.000 186.850 2.000 187.150 ;
    END
  END sram_idata[6]
  PIN sram_idata[7]
    DIRECTION OUTPUT ;
    USE SIGNAL ;
    ANTENNADIFFAREA 1.237600 ;
    PORT
      LAYER Metal3 ;
        RECT 0.000 222.850 2.000 223.150 ;
    END
  END sram_idata[7]
  PIN sram_odata[0]
    DIRECTION INPUT ;
    USE SIGNAL ;
    ANTENNAGATEAREA 1.999200 ;
    PORT
      LAYER Metal3 ;
        RECT 0.000 5.850 2.000 6.150 ;
    END
  END sram_odata[0]
  PIN sram_odata[1]
    DIRECTION INPUT ;
    USE SIGNAL ;
    ANTENNAGATEAREA 1.999200 ;
    PORT
      LAYER Metal3 ;
        RECT 0.000 32.850 2.000 33.150 ;
    END
  END sram_odata[1]
  PIN sram_odata[2]
    DIRECTION INPUT ;
    USE SIGNAL ;
    ANTENNAGATEAREA 1.999200 ;
    PORT
      LAYER Metal3 ;
        RECT 0.000 41.850 2.000 42.150 ;
    END
  END sram_odata[2]
  PIN sram_odata[3]
    DIRECTION INPUT ;
    USE SIGNAL ;
    ANTENNAGATEAREA 1.999200 ;
    ANTENNADIFFAREA 0.877000 ;
    PORT
      LAYER Metal3 ;
        RECT 0.000 69.850 2.000 70.150 ;
    END
  END sram_odata[3]
  PIN sram_odata[4]
    DIRECTION INPUT ;
    USE SIGNAL ;
    ANTENNAGATEAREA 1.999200 ;
    PORT
      LAYER Metal3 ;
        RECT 0.000 211.850 2.000 212.150 ;
    END
  END sram_odata[4]
  PIN sram_odata[5]
    DIRECTION INPUT ;
    USE SIGNAL ;
    ANTENNAGATEAREA 1.999200 ;
    PORT
      LAYER Metal3 ;
        RECT 0.000 178.850 2.000 179.150 ;
    END
  END sram_odata[5]
  PIN sram_odata[6]
    DIRECTION INPUT ;
    USE SIGNAL ;
    ANTENNAGATEAREA 1.999200 ;
    PORT
      LAYER Metal3 ;
        RECT 0.000 189.850 2.000 190.150 ;
    END
  END sram_odata[6]
  PIN sram_odata[7]
    DIRECTION INPUT ;
    USE SIGNAL ;
    ANTENNAGATEAREA 1.999200 ;
    PORT
      LAYER Metal3 ;
        RECT 0.000 217.850 2.000 218.150 ;
    END
  END sram_odata[7]
  PIN sram_read
    DIRECTION OUTPUT ;
    USE SIGNAL ;
    ANTENNADIFFAREA 1.439900 ;
    PORT
      LAYER Metal3 ;
        RECT 0.000 199.850 2.000 200.150 ;
    END
  END sram_read
  PIN sram_write
    DIRECTION OUTPUT ;
    USE SIGNAL ;
    ANTENNADIFFAREA 1.237600 ;
    PORT
      LAYER Metal3 ;
        RECT 0.000 133.850 2.000 134.150 ;
    END
  END sram_write
  PIN vddd
    DIRECTION INOUT ;
    USE POWER ;
    PORT
      LAYER Metal4 ;
        RECT 18.880 7.540 20.480 219.820 ;
    END
    PORT
      LAYER Metal4 ;
        RECT 172.480 7.540 174.080 219.820 ;
    END
    PORT
      LAYER Metal4 ;
        RECT 326.080 7.540 327.680 219.820 ;
    END
    PORT
      LAYER Metal4 ;
        RECT 479.680 7.540 481.280 219.820 ;
    END
    PORT
      LAYER Metal4 ;
        RECT 633.280 7.540 634.880 219.820 ;
    END
    PORT
      LAYER Metal4 ;
        RECT 786.880 7.540 788.480 219.820 ;
    END
    PORT
      LAYER Metal4 ;
        RECT 940.480 7.540 942.080 219.820 ;
    END
    PORT
      LAYER Metal4 ;
        RECT 1094.080 7.540 1095.680 219.820 ;
    END
    PORT
      LAYER Metal4 ;
        RECT 1247.680 7.540 1249.280 219.820 ;
    END
    PORT
      LAYER Metal4 ;
        RECT 1401.280 7.540 1402.880 219.820 ;
    END
    PORT
      LAYER Metal4 ;
        RECT 1554.880 7.540 1556.480 219.820 ;
    END
    PORT
      LAYER Metal4 ;
        RECT 1708.480 7.540 1710.080 219.820 ;
    END
    PORT
      LAYER Metal4 ;
        RECT 1862.080 7.540 1863.680 219.820 ;
    END
    PORT
      LAYER Metal4 ;
        RECT 2015.680 7.540 2017.280 219.820 ;
    END
    PORT
      LAYER Metal4 ;
        RECT 2169.280 7.540 2170.880 219.820 ;
    END
    PORT
      LAYER Metal4 ;
        RECT 2322.880 7.540 2324.480 219.820 ;
    END
    PORT
      LAYER Metal5 ;
        RECT 3.360 23.690 2436.560 25.290 ;
    END
    PORT
      LAYER Metal5 ;
        RECT 3.360 176.870 2436.560 178.470 ;
    END
  END vddd
  PIN voltgen_ena[0]
    DIRECTION OUTPUT ;
    USE SIGNAL ;
    ANTENNADIFFAREA 1.237600 ;
    PORT
      LAYER Metal2 ;
        RECT 1624.850 223.000 1625.150 225.000 ;
    END
  END voltgen_ena[0]
  PIN voltgen_ena[1]
    DIRECTION OUTPUT ;
    USE SIGNAL ;
    ANTENNADIFFAREA 1.237600 ;
    PORT
      LAYER Metal2 ;
        RECT 1626.850 223.000 1627.150 225.000 ;
    END
  END voltgen_ena[1]
  PIN voltgen_ena[2]
    DIRECTION OUTPUT ;
    USE SIGNAL ;
    ANTENNADIFFAREA 1.237600 ;
    PORT
      LAYER Metal2 ;
        RECT 1628.850 223.000 1629.150 225.000 ;
    END
  END voltgen_ena[2]
  PIN voltgen_high
    DIRECTION OUTPUT ;
    USE SIGNAL ;
    ANTENNADIFFAREA 1.237600 ;
    PORT
      LAYER Metal2 ;
        RECT 1630.850 223.000 1631.150 225.000 ;
    END
  END voltgen_high
  PIN voltgen_sink1[0]
    DIRECTION OUTPUT ;
    USE SIGNAL ;
    ANTENNADIFFAREA 1.237600 ;
    PORT
      LAYER Metal2 ;
        RECT 224.850 223.000 225.150 225.000 ;
    END
  END voltgen_sink1[0]
  PIN voltgen_sink1[1]
    DIRECTION OUTPUT ;
    USE SIGNAL ;
    ANTENNADIFFAREA 1.237600 ;
    PORT
      LAYER Metal2 ;
        RECT 227.850 223.000 228.150 225.000 ;
    END
  END voltgen_sink1[1]
  PIN voltgen_sink1[2]
    DIRECTION OUTPUT ;
    USE SIGNAL ;
    ANTENNADIFFAREA 1.237600 ;
    PORT
      LAYER Metal2 ;
        RECT 230.850 223.000 231.150 225.000 ;
    END
  END voltgen_sink1[2]
  PIN voltgen_sink2[0]
    DIRECTION OUTPUT ;
    USE SIGNAL ;
    ANTENNADIFFAREA 1.237600 ;
    PORT
      LAYER Metal2 ;
        RECT 233.850 223.000 234.150 225.000 ;
    END
  END voltgen_sink2[0]
  PIN voltgen_sink2[1]
    DIRECTION OUTPUT ;
    USE SIGNAL ;
    ANTENNADIFFAREA 1.237600 ;
    PORT
      LAYER Metal2 ;
        RECT 236.850 223.000 237.150 225.000 ;
    END
  END voltgen_sink2[1]
  PIN voltgen_sink2[2]
    DIRECTION OUTPUT ;
    USE SIGNAL ;
    ANTENNADIFFAREA 1.237600 ;
    PORT
      LAYER Metal2 ;
        RECT 239.850 223.000 240.150 225.000 ;
    END
  END voltgen_sink2[2]
  PIN voltgen_source[0]
    DIRECTION OUTPUT ;
    USE SIGNAL ;
    ANTENNADIFFAREA 1.237600 ;
    PORT
      LAYER Metal2 ;
        RECT 274.850 223.000 275.150 225.000 ;
    END
  END voltgen_source[0]
  PIN voltgen_source[1]
    DIRECTION OUTPUT ;
    USE SIGNAL ;
    ANTENNADIFFAREA 1.237600 ;
    PORT
      LAYER Metal2 ;
        RECT 277.850 223.000 278.150 225.000 ;
    END
  END voltgen_source[1]
  PIN voltgen_source[2]
    DIRECTION OUTPUT ;
    USE SIGNAL ;
    ANTENNADIFFAREA 1.237600 ;
    PORT
      LAYER Metal2 ;
        RECT 280.850 223.000 281.150 225.000 ;
    END
  END voltgen_source[2]
  PIN voltgen_source[3]
    DIRECTION OUTPUT ;
    USE SIGNAL ;
    ANTENNADIFFAREA 1.237600 ;
    PORT
      LAYER Metal2 ;
        RECT 283.850 223.000 284.150 225.000 ;
    END
  END voltgen_source[3]
  PIN voltgen_source[4]
    DIRECTION OUTPUT ;
    USE SIGNAL ;
    ANTENNADIFFAREA 1.237600 ;
    PORT
      LAYER Metal2 ;
        RECT 286.850 223.000 287.150 225.000 ;
    END
  END voltgen_source[4]
  PIN voltgen_value[0]
    DIRECTION OUTPUT ;
    USE SIGNAL ;
    ANTENNADIFFAREA 1.237600 ;
    PORT
      LAYER Metal2 ;
        RECT 1632.850 223.000 1633.150 225.000 ;
    END
  END voltgen_value[0]
  PIN voltgen_value[1]
    DIRECTION OUTPUT ;
    USE SIGNAL ;
    ANTENNADIFFAREA 1.237600 ;
    PORT
      LAYER Metal2 ;
        RECT 1634.850 223.000 1635.150 225.000 ;
    END
  END voltgen_value[1]
  PIN voltgen_value[2]
    DIRECTION OUTPUT ;
    USE SIGNAL ;
    ANTENNADIFFAREA 1.237600 ;
    PORT
      LAYER Metal2 ;
        RECT 1636.850 223.000 1637.150 225.000 ;
    END
  END voltgen_value[2]
  PIN vssd
    DIRECTION INOUT ;
    USE GROUND ;
    PORT
      LAYER Metal4 ;
        RECT 22.180 7.540 23.780 219.820 ;
    END
    PORT
      LAYER Metal4 ;
        RECT 175.780 7.540 177.380 219.820 ;
    END
    PORT
      LAYER Metal4 ;
        RECT 329.380 7.540 330.980 219.820 ;
    END
    PORT
      LAYER Metal4 ;
        RECT 482.980 7.540 484.580 219.820 ;
    END
    PORT
      LAYER Metal4 ;
        RECT 636.580 7.540 638.180 219.820 ;
    END
    PORT
      LAYER Metal4 ;
        RECT 790.180 7.540 791.780 219.820 ;
    END
    PORT
      LAYER Metal4 ;
        RECT 943.780 7.540 945.380 219.820 ;
    END
    PORT
      LAYER Metal4 ;
        RECT 1097.380 7.540 1098.980 219.820 ;
    END
    PORT
      LAYER Metal4 ;
        RECT 1250.980 7.540 1252.580 219.820 ;
    END
    PORT
      LAYER Metal4 ;
        RECT 1404.580 7.540 1406.180 219.820 ;
    END
    PORT
      LAYER Metal4 ;
        RECT 1558.180 7.540 1559.780 219.820 ;
    END
    PORT
      LAYER Metal4 ;
        RECT 1711.780 7.540 1713.380 219.820 ;
    END
    PORT
      LAYER Metal4 ;
        RECT 1865.380 7.540 1866.980 219.820 ;
    END
    PORT
      LAYER Metal4 ;
        RECT 2018.980 7.540 2020.580 219.820 ;
    END
    PORT
      LAYER Metal4 ;
        RECT 2172.580 7.540 2174.180 219.820 ;
    END
    PORT
      LAYER Metal4 ;
        RECT 2326.180 7.540 2327.780 219.820 ;
    END
    PORT
      LAYER Metal5 ;
        RECT 3.360 26.990 2436.560 28.590 ;
    END
    PORT
      LAYER Metal5 ;
        RECT 3.360 180.170 2436.560 181.770 ;
    END
  END vssd
  OBS
      LAYER Nwell ;
        RECT 2.930 7.410 2436.990 219.950 ;
      LAYER Metal1 ;
        RECT 3.360 7.540 2436.560 219.820 ;
      LAYER Metal2 ;
        RECT 0.140 222.700 4.550 223.910 ;
        RECT 5.450 222.700 24.550 223.910 ;
        RECT 25.450 222.700 27.550 223.910 ;
        RECT 28.450 222.700 30.550 223.910 ;
        RECT 31.450 222.700 33.550 223.910 ;
        RECT 34.450 222.700 36.550 223.910 ;
        RECT 37.450 222.700 74.550 223.910 ;
        RECT 75.450 222.700 77.550 223.910 ;
        RECT 78.450 222.700 80.550 223.910 ;
        RECT 81.450 222.700 83.550 223.910 ;
        RECT 84.450 222.700 86.550 223.910 ;
        RECT 87.450 222.700 124.550 223.910 ;
        RECT 125.450 222.700 127.550 223.910 ;
        RECT 128.450 222.700 130.550 223.910 ;
        RECT 131.450 222.700 133.550 223.910 ;
        RECT 134.450 222.700 174.550 223.910 ;
        RECT 175.450 222.700 177.550 223.910 ;
        RECT 178.450 222.700 180.550 223.910 ;
        RECT 181.450 222.700 183.550 223.910 ;
        RECT 184.450 222.700 186.550 223.910 ;
        RECT 187.450 222.700 224.550 223.910 ;
        RECT 225.450 222.700 227.550 223.910 ;
        RECT 228.450 222.700 230.550 223.910 ;
        RECT 231.450 222.700 233.550 223.910 ;
        RECT 234.450 222.700 236.550 223.910 ;
        RECT 237.450 222.700 239.550 223.910 ;
        RECT 240.450 222.700 274.550 223.910 ;
        RECT 275.450 222.700 277.550 223.910 ;
        RECT 278.450 222.700 280.550 223.910 ;
        RECT 281.450 222.700 283.550 223.910 ;
        RECT 284.450 222.700 286.550 223.910 ;
        RECT 287.450 222.700 644.550 223.910 ;
        RECT 645.450 222.700 646.550 223.910 ;
        RECT 647.450 222.700 648.550 223.910 ;
        RECT 649.450 222.700 650.550 223.910 ;
        RECT 651.450 222.700 652.550 223.910 ;
        RECT 653.450 222.700 654.550 223.910 ;
        RECT 655.450 222.700 656.550 223.910 ;
        RECT 657.450 222.700 658.550 223.910 ;
        RECT 659.450 222.700 660.550 223.910 ;
        RECT 661.450 222.700 662.550 223.910 ;
        RECT 663.450 222.700 664.550 223.910 ;
        RECT 665.450 222.700 666.550 223.910 ;
        RECT 667.450 222.700 864.550 223.910 ;
        RECT 865.450 222.700 1294.550 223.910 ;
        RECT 1295.450 222.700 1296.550 223.910 ;
        RECT 1297.450 222.700 1298.550 223.910 ;
        RECT 1299.450 222.700 1300.550 223.910 ;
        RECT 1301.450 222.700 1302.550 223.910 ;
        RECT 1303.450 222.700 1304.550 223.910 ;
        RECT 1305.450 222.700 1306.550 223.910 ;
        RECT 1307.450 222.700 1308.550 223.910 ;
        RECT 1309.450 222.700 1310.550 223.910 ;
        RECT 1311.450 222.700 1312.550 223.910 ;
        RECT 1313.450 222.700 1314.550 223.910 ;
        RECT 1315.450 222.700 1316.550 223.910 ;
        RECT 1317.450 222.700 1366.550 223.910 ;
        RECT 1367.450 222.700 1374.550 223.910 ;
        RECT 1375.450 222.700 1384.550 223.910 ;
        RECT 1385.450 222.700 1394.550 223.910 ;
        RECT 1395.450 222.700 1396.550 223.910 ;
        RECT 1397.450 222.700 1398.550 223.910 ;
        RECT 1399.450 222.700 1400.550 223.910 ;
        RECT 1401.450 222.700 1402.550 223.910 ;
        RECT 1403.450 222.700 1404.550 223.910 ;
        RECT 1405.450 222.700 1406.550 223.910 ;
        RECT 1407.450 222.700 1408.550 223.910 ;
        RECT 1409.450 222.700 1410.550 223.910 ;
        RECT 1411.450 222.700 1412.550 223.910 ;
        RECT 1413.450 222.700 1414.550 223.910 ;
        RECT 1415.450 222.700 1416.550 223.910 ;
        RECT 1417.450 222.700 1418.550 223.910 ;
        RECT 1419.450 222.700 1420.550 223.910 ;
        RECT 1421.450 222.700 1422.550 223.910 ;
        RECT 1423.450 222.700 1424.550 223.910 ;
        RECT 1425.450 222.700 1426.550 223.910 ;
        RECT 1427.450 222.700 1428.550 223.910 ;
        RECT 1429.450 222.700 1430.550 223.910 ;
        RECT 1431.450 222.700 1432.550 223.910 ;
        RECT 1433.450 222.700 1434.550 223.910 ;
        RECT 1435.450 222.700 1436.550 223.910 ;
        RECT 1437.450 222.700 1438.550 223.910 ;
        RECT 1439.450 222.700 1440.550 223.910 ;
        RECT 1441.450 222.700 1444.550 223.910 ;
        RECT 1445.450 222.700 1446.550 223.910 ;
        RECT 1447.450 222.700 1448.550 223.910 ;
        RECT 1449.450 222.700 1450.550 223.910 ;
        RECT 1451.450 222.700 1452.550 223.910 ;
        RECT 1453.450 222.700 1454.550 223.910 ;
        RECT 1455.450 222.700 1456.550 223.910 ;
        RECT 1457.450 222.700 1458.550 223.910 ;
        RECT 1459.450 222.700 1460.550 223.910 ;
        RECT 1461.450 222.700 1462.550 223.910 ;
        RECT 1463.450 222.700 1464.550 223.910 ;
        RECT 1465.450 222.700 1468.550 223.910 ;
        RECT 1469.450 222.700 1470.550 223.910 ;
        RECT 1471.450 222.700 1472.550 223.910 ;
        RECT 1473.450 222.700 1474.550 223.910 ;
        RECT 1475.450 222.700 1524.550 223.910 ;
        RECT 1525.450 222.700 1526.550 223.910 ;
        RECT 1527.450 222.700 1528.550 223.910 ;
        RECT 1529.450 222.700 1530.550 223.910 ;
        RECT 1531.450 222.700 1532.550 223.910 ;
        RECT 1533.450 222.700 1534.550 223.910 ;
        RECT 1535.450 222.700 1536.550 223.910 ;
        RECT 1537.450 222.700 1538.550 223.910 ;
        RECT 1539.450 222.700 1540.550 223.910 ;
        RECT 1541.450 222.700 1542.550 223.910 ;
        RECT 1543.450 222.700 1544.550 223.910 ;
        RECT 1545.450 222.700 1546.550 223.910 ;
        RECT 1547.450 222.700 1624.550 223.910 ;
        RECT 1625.450 222.700 1626.550 223.910 ;
        RECT 1627.450 222.700 1628.550 223.910 ;
        RECT 1629.450 222.700 1630.550 223.910 ;
        RECT 1631.450 222.700 1632.550 223.910 ;
        RECT 1633.450 222.700 1634.550 223.910 ;
        RECT 1635.450 222.700 1636.550 223.910 ;
        RECT 1637.450 222.700 1724.550 223.910 ;
        RECT 1725.450 222.700 1726.550 223.910 ;
        RECT 1727.450 222.700 1728.550 223.910 ;
        RECT 1729.450 222.700 1730.550 223.910 ;
        RECT 1731.450 222.700 1732.550 223.910 ;
        RECT 1733.450 222.700 1734.550 223.910 ;
        RECT 1735.450 222.700 1736.550 223.910 ;
        RECT 1737.450 222.700 1738.550 223.910 ;
        RECT 1739.450 222.700 1740.550 223.910 ;
        RECT 1741.450 222.700 1742.550 223.910 ;
        RECT 1743.450 222.700 1744.550 223.910 ;
        RECT 1745.450 222.700 1746.550 223.910 ;
        RECT 1747.450 222.700 1748.550 223.910 ;
        RECT 1749.450 222.700 1750.550 223.910 ;
        RECT 1751.450 222.700 1752.550 223.910 ;
        RECT 1753.450 222.700 1754.550 223.910 ;
        RECT 1755.450 222.700 1756.550 223.910 ;
        RECT 1757.450 222.700 2412.340 223.910 ;
        RECT 0.140 2.300 2412.340 222.700 ;
        RECT 0.140 0.090 4.550 2.300 ;
        RECT 5.450 0.090 7.550 2.300 ;
        RECT 8.450 0.090 10.550 2.300 ;
        RECT 11.450 0.090 13.550 2.300 ;
        RECT 14.450 0.090 188.550 2.300 ;
        RECT 189.450 0.090 391.550 2.300 ;
        RECT 392.450 0.090 804.550 2.300 ;
        RECT 805.450 0.090 806.550 2.300 ;
        RECT 807.450 0.090 808.550 2.300 ;
        RECT 809.450 0.090 810.550 2.300 ;
        RECT 811.450 0.090 812.550 2.300 ;
        RECT 813.450 0.090 814.550 2.300 ;
        RECT 815.450 0.090 816.550 2.300 ;
        RECT 817.450 0.090 818.550 2.300 ;
        RECT 819.450 0.090 820.550 2.300 ;
        RECT 821.450 0.090 822.550 2.300 ;
        RECT 823.450 0.090 824.550 2.300 ;
        RECT 825.450 0.090 826.550 2.300 ;
        RECT 827.450 0.090 828.550 2.300 ;
        RECT 829.450 0.090 830.550 2.300 ;
        RECT 831.450 0.090 832.550 2.300 ;
        RECT 833.450 0.090 834.550 2.300 ;
        RECT 835.450 0.090 836.550 2.300 ;
        RECT 837.450 0.090 838.550 2.300 ;
        RECT 839.450 0.090 840.550 2.300 ;
        RECT 841.450 0.090 842.550 2.300 ;
        RECT 843.450 0.090 844.550 2.300 ;
        RECT 845.450 0.090 846.550 2.300 ;
        RECT 847.450 0.090 848.550 2.300 ;
        RECT 849.450 0.090 850.550 2.300 ;
        RECT 851.450 0.090 852.550 2.300 ;
        RECT 853.450 0.090 854.550 2.300 ;
        RECT 855.450 0.090 856.550 2.300 ;
        RECT 857.450 0.090 858.550 2.300 ;
        RECT 859.450 0.090 860.550 2.300 ;
        RECT 861.450 0.090 862.550 2.300 ;
        RECT 863.450 0.090 864.550 2.300 ;
        RECT 865.450 0.090 866.550 2.300 ;
        RECT 867.450 0.090 995.550 2.300 ;
        RECT 996.450 0.090 996.550 2.300 ;
        RECT 997.450 0.090 997.550 2.300 ;
        RECT 998.450 0.090 1197.550 2.300 ;
        RECT 1198.450 0.090 1198.550 2.300 ;
        RECT 1199.450 0.090 1199.550 2.300 ;
        RECT 1200.450 0.090 1399.550 2.300 ;
        RECT 1400.450 0.090 1400.550 2.300 ;
        RECT 1401.450 0.090 1401.550 2.300 ;
        RECT 1402.450 0.090 1601.550 2.300 ;
        RECT 1602.450 0.090 1602.550 2.300 ;
        RECT 1603.450 0.090 1603.550 2.300 ;
        RECT 1604.450 0.090 1803.550 2.300 ;
        RECT 1804.450 0.090 1804.550 2.300 ;
        RECT 1805.450 0.090 1805.550 2.300 ;
        RECT 1806.450 0.090 2005.550 2.300 ;
        RECT 2006.450 0.090 2006.550 2.300 ;
        RECT 2007.450 0.090 2007.550 2.300 ;
        RECT 2008.450 0.090 2207.550 2.300 ;
        RECT 2208.450 0.090 2208.550 2.300 ;
        RECT 2209.450 0.090 2209.550 2.300 ;
        RECT 2210.450 0.090 2409.550 2.300 ;
        RECT 2410.450 0.090 2410.550 2.300 ;
        RECT 2411.450 0.090 2411.550 2.300 ;
      LAYER Metal3 ;
        RECT 0.090 223.450 2412.390 223.860 ;
        RECT 2.300 222.550 2412.390 223.450 ;
        RECT 0.090 218.450 2412.390 222.550 ;
        RECT 2.300 217.550 2412.390 218.450 ;
        RECT 0.090 212.450 2412.390 217.550 ;
        RECT 2.300 211.550 2412.390 212.450 ;
        RECT 0.090 209.450 2412.390 211.550 ;
        RECT 2.300 208.550 2412.390 209.450 ;
        RECT 0.090 200.450 2412.390 208.550 ;
        RECT 2.300 199.550 2412.390 200.450 ;
        RECT 0.090 190.450 2412.390 199.550 ;
        RECT 2.300 189.550 2412.390 190.450 ;
        RECT 0.090 189.450 2412.390 189.550 ;
        RECT 2.300 188.550 2412.390 189.450 ;
        RECT 0.090 187.450 2412.390 188.550 ;
        RECT 2.300 186.550 2412.390 187.450 ;
        RECT 0.090 185.450 2412.390 186.550 ;
        RECT 2.300 184.550 2412.390 185.450 ;
        RECT 0.090 183.450 2412.390 184.550 ;
        RECT 2.300 182.550 2412.390 183.450 ;
        RECT 0.090 182.450 2412.390 182.550 ;
        RECT 2.300 181.550 2412.390 182.450 ;
        RECT 0.090 181.450 2412.390 181.550 ;
        RECT 2.300 180.550 2412.390 181.450 ;
        RECT 0.090 179.450 2412.390 180.550 ;
        RECT 2.300 178.550 2412.390 179.450 ;
        RECT 0.090 134.450 2412.390 178.550 ;
        RECT 2.300 133.550 2412.390 134.450 ;
        RECT 0.090 112.450 2412.390 133.550 ;
        RECT 2.300 111.550 2412.390 112.450 ;
        RECT 0.090 106.450 2412.390 111.550 ;
        RECT 2.300 105.550 2412.390 106.450 ;
        RECT 0.090 100.450 2412.390 105.550 ;
        RECT 2.300 99.550 2412.390 100.450 ;
        RECT 0.090 96.450 2412.390 99.550 ;
        RECT 2.300 95.550 2412.390 96.450 ;
        RECT 0.090 94.450 2412.390 95.550 ;
        RECT 2.300 93.550 2412.390 94.450 ;
        RECT 0.090 92.450 2412.390 93.550 ;
        RECT 2.300 91.550 2412.390 92.450 ;
        RECT 0.090 90.450 2412.390 91.550 ;
        RECT 2.300 89.550 2412.390 90.450 ;
        RECT 0.090 75.450 2412.390 89.550 ;
        RECT 2.300 74.550 2412.390 75.450 ;
        RECT 0.090 70.450 2412.390 74.550 ;
        RECT 2.300 69.550 2412.390 70.450 ;
        RECT 0.090 42.450 2412.390 69.550 ;
        RECT 2.300 41.550 2412.390 42.450 ;
        RECT 0.090 39.450 2412.390 41.550 ;
        RECT 2.300 38.550 2412.390 39.450 ;
        RECT 0.090 35.450 2412.390 38.550 ;
        RECT 2.300 34.550 2412.390 35.450 ;
        RECT 0.090 33.450 2412.390 34.550 ;
        RECT 2.300 32.550 2412.390 33.450 ;
        RECT 0.090 6.450 2412.390 32.550 ;
        RECT 2.300 5.550 2412.390 6.450 ;
        RECT 0.090 1.450 2412.390 5.550 ;
        RECT 2.300 0.550 2412.390 1.450 ;
        RECT 0.090 0.140 2412.390 0.550 ;
      LAYER Metal4 ;
        RECT 2.380 220.120 2400.020 222.790 ;
        RECT 2.380 7.240 18.580 220.120 ;
        RECT 20.780 7.240 21.880 220.120 ;
        RECT 24.080 7.240 172.180 220.120 ;
        RECT 174.380 7.240 175.480 220.120 ;
        RECT 177.680 7.240 325.780 220.120 ;
        RECT 327.980 7.240 329.080 220.120 ;
        RECT 331.280 7.240 479.380 220.120 ;
        RECT 481.580 7.240 482.680 220.120 ;
        RECT 484.880 7.240 632.980 220.120 ;
        RECT 635.180 7.240 636.280 220.120 ;
        RECT 638.480 7.240 786.580 220.120 ;
        RECT 788.780 7.240 789.880 220.120 ;
        RECT 792.080 7.240 940.180 220.120 ;
        RECT 942.380 7.240 943.480 220.120 ;
        RECT 945.680 7.240 1093.780 220.120 ;
        RECT 1095.980 7.240 1097.080 220.120 ;
        RECT 1099.280 7.240 1247.380 220.120 ;
        RECT 1249.580 7.240 1250.680 220.120 ;
        RECT 1252.880 7.240 1400.980 220.120 ;
        RECT 1403.180 7.240 1404.280 220.120 ;
        RECT 1406.480 7.240 1554.580 220.120 ;
        RECT 1556.780 7.240 1557.880 220.120 ;
        RECT 1560.080 7.240 1708.180 220.120 ;
        RECT 1710.380 7.240 1711.480 220.120 ;
        RECT 1713.680 7.240 1861.780 220.120 ;
        RECT 1863.980 7.240 1865.080 220.120 ;
        RECT 1867.280 7.240 2015.380 220.120 ;
        RECT 2017.580 7.240 2018.680 220.120 ;
        RECT 2020.880 7.240 2168.980 220.120 ;
        RECT 2171.180 7.240 2172.280 220.120 ;
        RECT 2174.480 7.240 2322.580 220.120 ;
        RECT 2324.780 7.240 2325.880 220.120 ;
        RECT 2328.080 7.240 2400.020 220.120 ;
        RECT 2.380 0.090 2400.020 7.240 ;
      LAYER Metal5 ;
        RECT 67.260 182.370 2400.100 216.670 ;
        RECT 67.260 179.070 2400.100 179.570 ;
        RECT 67.260 29.190 2400.100 176.270 ;
        RECT 67.260 25.890 2400.100 26.390 ;
        RECT 67.260 0.230 2400.100 23.090 ;
  END
END housekeeping_harness
END LIBRARY

